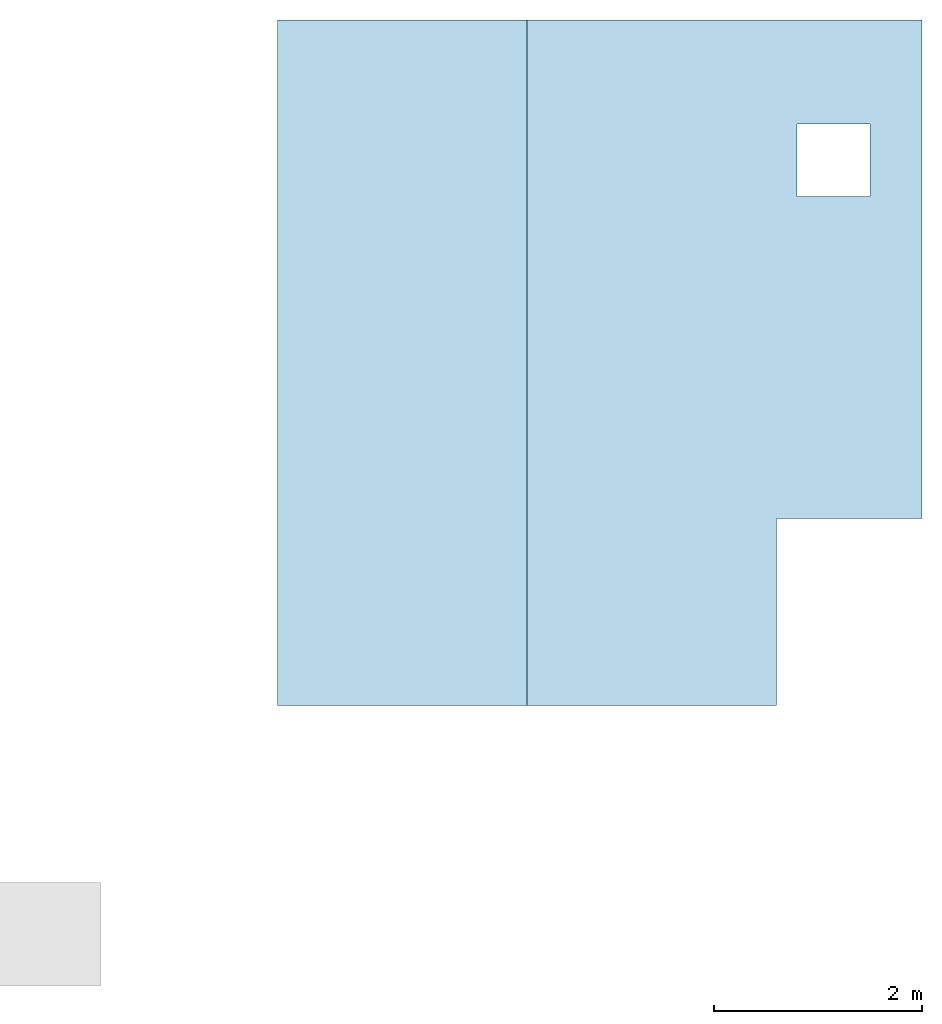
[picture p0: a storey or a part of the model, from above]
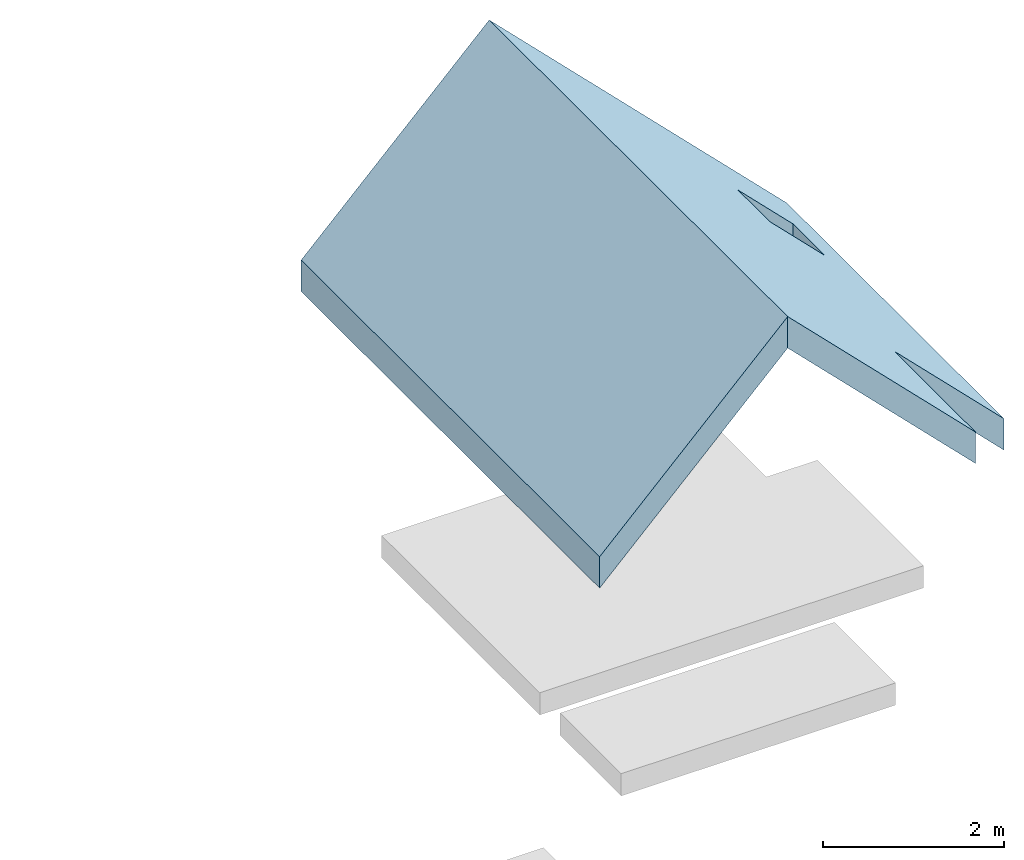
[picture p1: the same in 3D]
Properties of the parts of a building model (IFC4)

# File
Description: ViewDefinition [ReferenceView_V1.2]
File name: Building-Architecture.ifc
Time: 2024-11-14T11:09:12
Written by: IFC-manager for SketchUp (5.3.3)
Made in: SketchUp 2024 (24.0.594)

# IfcProject, ifc silly sample scene - project
Description: Demystifying IFC with a playful scene using diverse building elements and compositions.

# IfcSite (2)
RefElevation: 0 mm
Name | Description
environment - site | A sample scene environment, showcasing the surrounding landscape.
house - site | Smoke curls from a friendly chimney, promising warmth within this idyllic hilltop house.

# IfcBuilding, Single-family house
Description: The main building structure, providing shelter and space.; LongName: house - building; Classification: E-AAA Single-family house (CCI Construction)
Pset_BuildingCommon - ConstructionMethod: new construction

# IfcBuildingStorey, 00 groundfloor
In: Single-family house
Description: The ground floor, forming the base level of the building.; Elevation: -1.80478e-12 mm

# IfcSpace: house - entry hall, entry hall
In: 00 groundfloor
Type - Description: A welcoming entry hall, the first impression of the home.; ElementType: hallway; LongName: entry hall
ElevationWithFlooring: 0 mm; Group: house - living space
Pset_SpaceCommon - IsExternal: no; GrossPlannedArea: 6.08 m2; NetPlannedArea: 6.08 m2; PubliclyAccessible: no; HandicapAccessible: no

# IfcSpace: house - living room, living room
In: 00 groundfloor
Type - Description: A cozy space, perfect for relaxation and family gatherings.; ElementType: living area; LongName: living room
ElevationWithFlooring: 0 mm; Group: house - living space
Pset_SpaceCommon - IsExternal: no; GrossPlannedArea: 18.5 m2; NetPlannedArea: 18.5 m2; PubliclyAccessible: no; HandicapAccessible: no

# IfcBuildingElementProxy (2)
Material: Default
Name | In
Group#18 | living room
Group#19 | 00 groundfloor

# IfcBuildingElementProxy: geo-reference
In: environment - site
Type - Description: The reference point for transforming the local engineering coordinate system into the coordinate reference system of the underlying map.; ElementType: origin; PredefinedType: USERDEFINED
Material: virtual_black

# IfcBuildingElementProxy: origin
In: house - site
Type - Description: The local position for coordination of aspect models.; ElementType: origin; PredefinedType: USERDEFINED
Material: virtual_white

# IfcBuildingElementProxy: sand bedding
In: Single-family house
Type - Description: A layer of ground floor sand bedding, providing a stable base.; ElementType: subgrade; PredefinedType: ELEMENT
Material: bulk-material_sand-coarse_generic

# IfcChimney: house - chimney
In: 00 groundfloor
Type - Description: A chimney, standing tall and proud, guiding smoke away from the home.; ElementType: flue; PredefinedType: USERDEFINED
Material: stone_sand-lime

# IfcFurniture: house - kitchen, kitchen
In: living room
Type - Description: The heart of the home, where meals are prepared and shared.; ElementType: kitchen; PredefinedType: USERDEFINED
Material: wood_mdf_plate

# IfcRoof: house - roof
In: Single-family house
Type - Description: A sturdy roof, sheltering the house from the elements.; ElementType: gable_roof; PredefinedType: GABLE_ROOF
Pset_RoofCommon - IsExternal: yes

# IfcSlab: house - groundfloor, floor
In: 00 groundfloor
Type - Description: A solid, site-cast concrete floor, providing a strong foundation.; ElementType: slab on grade; PredefinedType: FLOOR
Material: concrete_reinforced_in-situ
Pset_SlabCommon - IsExternal: yes; LoadBearing: no
Qto_SlabBaseQuantities - NetVolume: 6.4375 m3; Depth: 250 mm; NetArea: 25.75 m2

# IfcSlab: house - roof - slab left
In: Single-family house
Type - Description: A roof slab that's got it all covered; ElementType: roof; PredefinedType: ROOF
Material: composite_element_roof
Pset_SlabCommon - PitchAngle: 45; IsExternal: yes; LoadBearing: no
Qto_SlabBaseQuantities - NetVolume: 6.72034 m3; Depth: 300 mm; NetArea: 22.4011 m2

# IfcSlab: house - roof - slab right
In: Single-family house
Type - Description: A roof slab that's got it all covered; ElementType: roof; PredefinedType: ROOF
Material: composite_element_roof
Pset_SlabCommon - IsExternal: yes; LoadBearing: no
Qto_SlabBaseQuantities - NetVolume: 9.36351 m3; Depth: 300 mm; NetArea: 31.2117 m2

# IfcSpatialZone: house - gross volume
Type - ElementType: gross volume; PredefinedType: USERDEFINED

# IfcWall: house - outer wall - house left
In: 00 groundfloor
Type - Description: A solid outer wall, forming the left side of the house.; ElementType: solidwall; PredefinedType: SOLIDWALL
Material: stone_sand-lime
Pset_WallCommon - IsExternal: yes; LoadBearing: no
Qto_WallBaseQuantities - NetVolume: 4.23088 m3; Width: 200 mm; Length: 6000 mm; NetSideArea: 21.1544 m2

# IfcWall: house - outer wall - house right back
In: 00 groundfloor
Type - Description: A solid outer wall, forming the right back side of the house.; ElementType: solidwall; PredefinedType: SOLIDWALL
Material: stone_sand-lime
Pset_WallCommon - IsExternal: yes; LoadBearing: no
Qto_WallBaseQuantities - NetVolume: 1.78562 m3; Width: 200 mm; Length: 4200 mm; NetSideArea: 8.92809 m2

# IfcWall: house - outer wall - house right front
In: 00 groundfloor
Type - Description: A solid outer wall, forming the right front side of the house.; ElementType: solidwall; PredefinedType: SOLIDWALL
Material: stone_sand-lime
Pset_WallCommon - IsExternal: yes; LoadBearing: no
Qto_WallBaseQuantities - NetVolume: 1.26926 m3; Width: 200 mm; Length: 1800 mm; NetSideArea: 6.34632 m2

# IfcWall: plumbing wall
In: 00 groundfloor
Type - Description: A wall designed to house and protect plumbing systems, keeping the pipes snug and secure.; ElementType: plumbingwall; PredefinedType: PLUMBINGWALL
Material: gypsum_fiber-board_panel
Pset_WallCommon - IsExternal: no; LoadBearing: no
Qto_WallBaseQuantities - NetVolume: 0.164702 m3; Width: 24 mm; Length: 3800 mm; NetSideArea: 6.86258 m2

# IfcZone, house - living space
Description: A cozy living space, perfect for relaxation and gatherings.
Pset_ZoneCommon - IsExternal: no; PubliclyAccessible: no; HandicapAccessible: no
